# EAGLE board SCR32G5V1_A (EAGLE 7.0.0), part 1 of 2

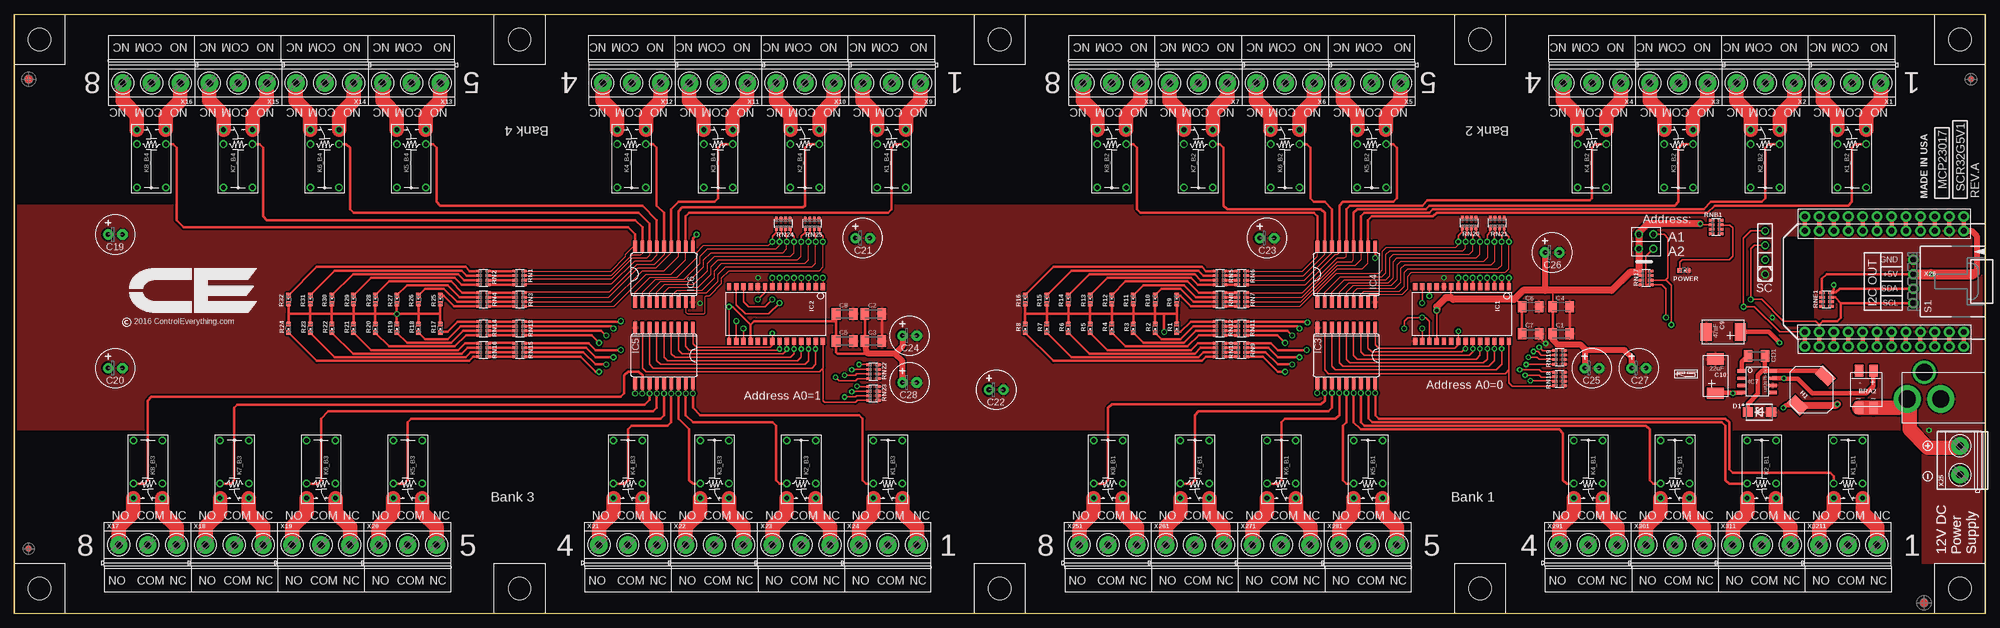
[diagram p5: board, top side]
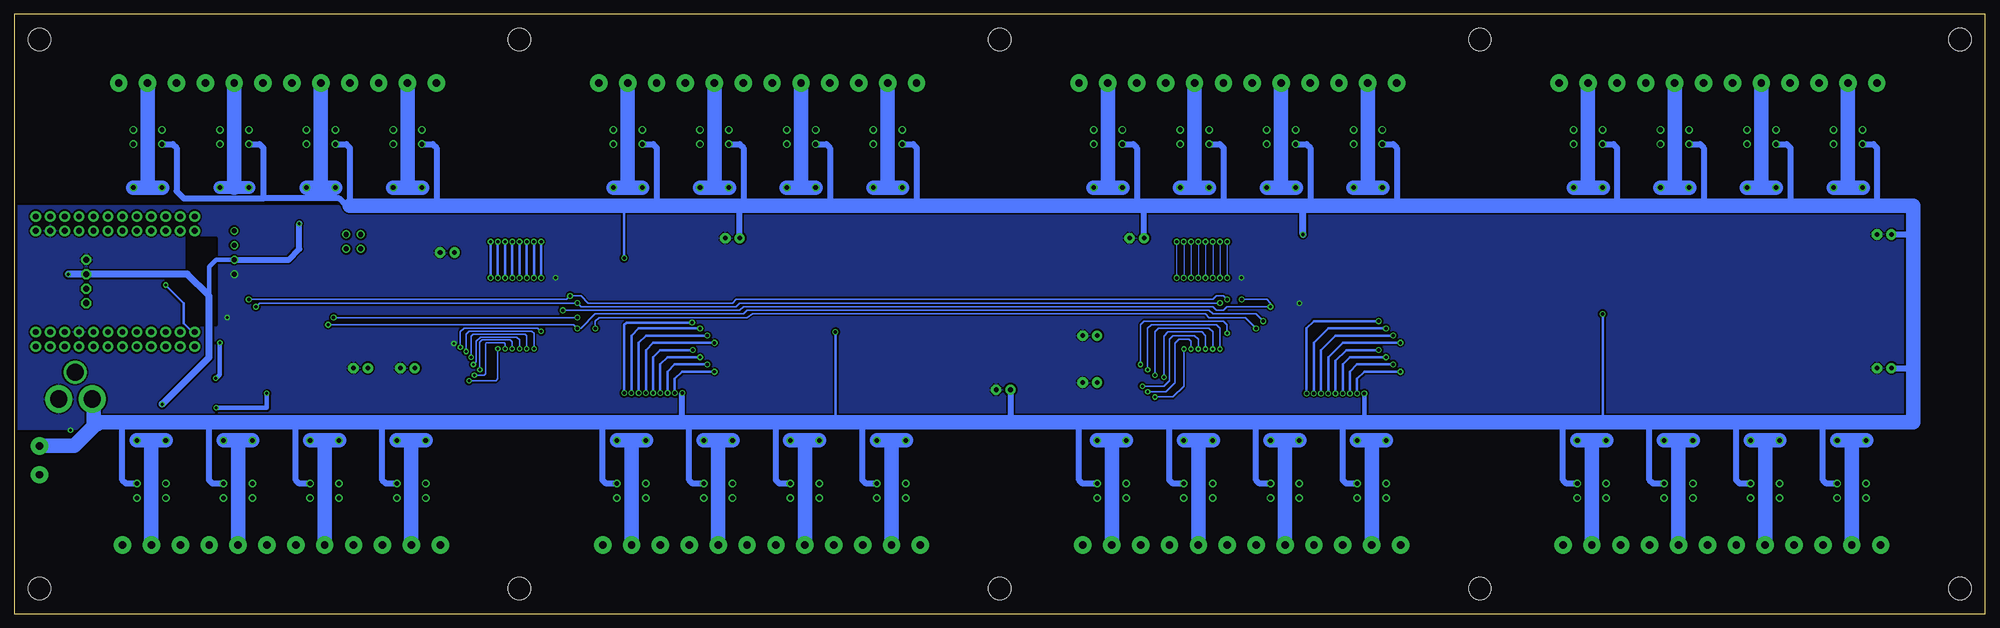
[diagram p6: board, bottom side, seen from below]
Size 346.69 x 105.42 mm. Coordinates in mm from the lower left corner, seen from the top.
Outline: 0,105.42 346.69,105.42 346.69,0 0,0 0,105.42
Copper layers (1*16): Top 0.035mm / dielectric 1.5mm / Bottom 0.035mm
Design rules "default *": minimum track width 6mil, minimum drill 12mil, track to track 5mil, track to pad 5mil, pad to pad 5mil, via to via 5mil, smd to smd 5mil, copper to edge 20mil, drill to drill 8mil, minimum pad ring 10mil, minimum via ring 8mil, stop-mask expansion 4mil, vias tented up to drill 0mil, thermal gap 10mil

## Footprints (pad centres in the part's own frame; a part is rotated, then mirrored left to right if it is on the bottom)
MB2S = smd 1.55 x 2.1: + 0,-6.5; - 2.54,-6.5; ~@1 0,0; ~@2 2.54,0
_CA_.1UF_50V = smd 1.5 x 2: 1 -1.5,0; 2 1.5,0
_CB_10UF_25V = smd 1.5 x 2: 1 -1.5,0; 2 1.5,0
C2917(7343)-Y = smd 2 x 3: 1 -3,0; 2 3,0
E-025X060 = drill 0.813 pad 1.778: + -1.27,0 | drill 0.813 pad 1.778 octagon: - 1.27,0
_CD_10NF_50V = smd 1.5 x 2: 1 -1.5,0; 2 1.5,0
DO214AC_ZENER = smd 1.8 x 1.7: A 2.05,0; C -2.05,0
IND_ELL8TP = smd 2.054 x 3.2 rotated 45: 1 -2.442,-2.696; 2 2.442,2.442
SO28W = smd 0.762 x 1.27: 1 -7.62,-4.78; 2 -6.35,-4.78; 3 -5.08,-4.78; 4 -3.81,-4.78; 5 -2.54,-4.78; 6 -1.27,-4.78; 7 0,-4.78; 8 1.27,-4.78; 9 2.54,-4.78; 10 3.81,-4.78; 11 5.08,-4.78; 12 6.35,-4.78; 13 7.62,-4.78; 14 8.89,-4.78; 15 8.89,4.78; 16 7.62,4.78; 17 6.35,4.78; 18 5.08,4.78; 19 3.81,4.78; 20 2.54,4.78; 21 1.27,4.78; 22 0,4.78; 23 -1.27,4.78; 24 -2.54,4.78; 25 -3.81,4.78; 26 -5.08,4.78; 27 -6.35,4.78; 28 -7.62,4.78
SO18L = smd 0.66 x 2.032: 1 -5.08,-4.902; 2 -3.81,-4.902; 3 -2.54,-4.902; 4 -1.27,-4.902; 5 0,-4.902; 6 1.27,-4.902; 7 2.54,-4.902; 8 3.81,-4.902; 9 5.08,-4.902; 10 5.08,4.902; 11 3.81,4.902; 12 2.54,4.902; 13 1.27,4.902; 14 0,4.902; 15 -1.27,4.902; 16 -2.54,4.902; 17 -3.81,4.902; 18 -5.08,4.902
SO-8 = smd 0.6 x 1.55: 1 -1.905,-2.69; 2 -0.635,-2.69; 3 0.635,-2.69; 4 1.905,-2.69; 5 1.905,2.71; 6 0.635,2.71; 7 -0.635,2.71; 8 -1.905,2.71
G5V1 = drill 0.813: C1 -2.54,2.54; C2 -2.54,-2.54; COM@1 5.08,-2.54; COM@2 5.08,2.54; NC -5.08,-2.54; NO -5.08,2.54
CHIPLED_0603 = smd 0.8 x 0.8: A 0,-0.75; C 0,0.75
RNB = smd 0.5 x 0.9: 1 -1.2,-0.8; 2 -0.4,-0.8; 3 0.4,-0.8; 4 1.2,-0.8; 5 1.2,0.8; 6 0.4,0.8; 7 -0.4,0.8; 8 -1.2,0.8
RNE = smd 0.5 x 0.9: 1 -1.2,-0.8; 2 -0.4,-0.8; 3 0.4,-0.8; 4 1.2,-0.8; 5 1.2,0.8; 6 0.4,0.8; 7 -0.4,0.8; 8 -1.2,0.8
RND = smd 0.5 x 0.9: 1 -1.2,-0.8; 2 -0.4,-0.8; 3 0.4,-0.8; 4 1.2,-0.8; 5 1.2,0.8; 6 0.4,0.8; 7 -0.4,0.8; 8 -1.2,0.8
SPARK_CORE = drill 1.016 pad 1.88: 1 -8.89,13.97; 2 -8.89,11.43; 3 -8.89,8.89; 4 -8.89,6.35; 5 -8.89,3.81; 6 -8.89,1.27; 7 -8.89,-1.27; 8 -8.89,-3.81; 9 -8.89,-6.35; 10 -8.89,-8.89; 11 -8.89,-11.43; 12 -8.89,-13.97; 13 8.89,-13.97; 14 8.89,-11.43; 15 8.89,-8.89; 16 8.89,-6.35; 17 8.89,-3.81; 18 8.89,-1.27; 19 8.89,1.27; 20 8.89,3.81; 21 8.89,6.35; 22 8.89,8.89; 23 8.89,11.43; 24 8.89,13.97; 25 -11.43,13.97; 26 -11.43,11.43; 27 -11.43,8.89; 28 -11.43,6.35; 29 -11.43,3.81; 30 -11.43,1.27; 31 -11.43,-1.27; 32 -11.43,-3.81; 33 -11.43,-6.35; 34 -11.43,-8.89; 35 -11.43,-11.43; 36 -11.43,-13.97; 37 11.43,13.97; 38 11.43,11.43; 39 11.43,8.89; 40 11.43,6.35; 41 11.43,3.81; 42 11.43,1.27; 43 11.43,-1.27; 44 11.43,-3.81; 45 11.43,-6.35; 46 11.43,-8.89; 47 11.43,-11.43; 48 11.43,-13.97
PCB_MOUNTING_HOLE = hole 3.962: 4.445,4.445
JUMPER_2X2 = drill 0.9: A1 0,2.54; A2 0,0; B1 2.54,2.54; B2 2.54,0
PJ-102A = drill 3 pad 4.8: RING 0.1,-3.39; TIP 0.1,-9.29 | drill 3 pad 3.251: RING_SW -4.6,-6.29
MKDSN1,5/3-5,08 = drill 1.3 pad 3.048: 1 -7.641,0.025; 2 -2.561,0.025; 3 2.519,0.025
MKDSN1,5/2-5,08 = drill 1.3 pad 3.048: 1 -2.561,0.025; 2 2.519,0.025
15-91-04 = drill 1.1 pad 1.778 octagon: 1 -3.81,-7.62; 2 -1.27,-7.62; 3 1.27,-7.62; 4 3.81,-7.62

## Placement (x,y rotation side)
BRA2  MB2S_  [MB2S]  327.02,36.21 180 top
C1  [_CA_.1UF_50V]  272.1,49.22 0 top
C2  _CB_10UF_25VC1206K  [_CB_10UF_25V]  151.13,52.72 0 top
C3  [_CA_.1UF_50V]  151.13,47.95 0 top
C4  _CB_10UF_25VC1206K  [_CB_10UF_25V]  272.1,53.99 0 top
C5  [_CA_.1UF_50V]  146.05,47.95 0 top
C6  _CB_10UF_25VC1206K  [_CB_10UF_25V]  266.7,53.99 0 top
C7  [_CA_.1UF_50V]  266.7,49.22 0 top
C8  _CB_10UF_25VC1206K  [_CB_10UF_25V]  146.05,52.72 0 top
C9  47uF  [C2917(7343)-Y]  300.61,49.54 180 top
C10  22uF  [C2917(7343)-Y]  299.21,41.77 90 top
C19  100uF  [E-025X060]  17.78,66.69 0 top
C20  100uF  [E-025X060]  17.78,43.19 0 top
C21  100uF  [E-025X060]  149.22,66.05 0 top
C22  100uF  [E-025X060]  172.72,39.38 0 top
C23  100uF  [E-025X060]  220.34,66.05 0 top
C24  100uF  [E-025X060]  157.48,48.91 0 top
C25  100uF  [E-025X060]  277.5,43.19 0 top
C26  100uF  [E-025X060]  270.51,63.51 0 top
C27  100uF  [E-025X060]  285.75,43.19 0 top
C28  100uF  [E-025X060]  157.48,40.65 0 top
CD1  [_CD_10NF_50V]  306.45,45.35 0 top
D1  B360A  [DO214AC_ZENER]  306.96,35.45 0 top
H1  ELL8TP  [IND_ELL8TP]  316.1,39.38 0 top
IC1  MCP23017SO  [SO28W]  255.27,52.72 180 top
IC2  MCP23017SO  [SO28W]  134.62,52.72 180 top
IC3  ULN2803  [SO18L]  234.31,45.42 180 top
IC4  ULN2803  [SO18L]  234.31,59.7 0 top
IC5  ULN2803  [SO18L]  114.3,45.42 180 top
IC6  ULN2803  [SO18L]  114.3,59.7 0 top
IC7  LM2675-5V  [SO-8]  306.58,40.78 270 top
K1_B1  G5V1  [G5V1]  322.58,25.41 90 top
K1_B2  G5V1  [G5V1]  323.21,80.02 270 top
K1_B3  G5V1  [G5V1]  153.67,25.41 90 top
K1_B4  G5V1  [G5V1]  154.31,80.02 270 top
K2_B1  G5V1  [G5V1]  307.34,25.41 90 top
K2_B2  G5V1  [G5V1]  307.98,80.02 270 top
K2_B3  G5V1  [G5V1]  138.43,25.41 90 top
K2_B4  G5V1  [G5V1]  139.06,80.02 270 top
K3_B1  G5V1  [G5V1]  292.1,25.41 90 top
K3_B2  G5V1  [G5V1]  292.74,80.02 270 top
K3_B3  G5V1  [G5V1]  123.19,25.41 90 top
K3_B4  G5V1  [G5V1]  123.83,80.02 270 top
K4_B1  G5V1  [G5V1]  276.86,25.41 90 top
K4_B2  G5V1  [G5V1]  277.5,80.02 270 top
K4_B3  G5V1  [G5V1]  107.95,25.41 90 top
K4_B4  G5V1  [G5V1]  108.58,80.02 270 top
K5_B1  G5V1  [G5V1]  238.12,25.41 90 top
K5_B2  G5V1  [G5V1]  238.76,80.02 270 top
K5_B3  G5V1  [G5V1]  69.22,25.41 90 top
K5_B4  G5V1  [G5V1]  69.85,80.02 270 top
K6_B1  G5V1  [G5V1]  222.88,25.41 90 top
K6_B2  G5V1  [G5V1]  223.52,80.02 270 top
K6_B3  G5V1  [G5V1]  53.98,25.41 90 top
K6_B4  G5V1  [G5V1]  54.61,80.02 270 top
K7_B1  G5V1  [G5V1]  207.65,25.41 90 top
K7_B2  G5V1  [G5V1]  208.28,80.02 270 top
K7_B3  G5V1  [G5V1]  38.73,25.41 90 top
K7_B4  G5V1  [G5V1]  39.37,80.02 270 top
K8_B1  G5V1  [G5V1]  192.41,25.41 90 top
K8_B2  G5V1  [G5V1]  193.04,80.02 270 top
K8_B3  G5V1  [G5V1]  23.5,25.41 90 top
K8_B4  G5V1  [G5V1]  24.13,80.02 270 top
POWER  LED_NCD  [CHIPLED_0603]  293.69,60.34 270 top
R1  LED_NCD  [CHIPLED_0603]  204.47,50.18 180 top
R2  LED_NCD  [CHIPLED_0603]  200.66,50.18 180 top
R3  LED_NCD  [CHIPLED_0603]  196.85,50.18 180 top
R4  LED_NCD  [CHIPLED_0603]  193.04,50.18 180 top
R5  LED_NCD  [CHIPLED_0603]  189.23,50.18 180 top
R6  LED_NCD  [CHIPLED_0603]  185.42,50.18 180 top
R7  LED_NCD  [CHIPLED_0603]  181.61,50.18 180 top
R8  LED_NCD  [CHIPLED_0603]  177.8,50.18 180 top
R9  LED_NCD  [CHIPLED_0603]  204.47,55.26 0 top
R10  LED_NCD  [CHIPLED_0603]  200.66,55.26 0 top
R11  LED_NCD  [CHIPLED_0603]  196.85,55.26 0 top
R12  LED_NCD  [CHIPLED_0603]  193.04,55.26 0 top
R13  LED_NCD  [CHIPLED_0603]  189.23,55.26 0 top
R14  LED_NCD  [CHIPLED_0603]  185.42,55.26 0 top
R15  LED_NCD  [CHIPLED_0603]  181.61,55.26 0 top
R16  LED_NCD  [CHIPLED_0603]  177.8,55.26 0 top
R17  LED_NCD  [CHIPLED_0603]  74.93,50.18 180 top
R18  LED_NCD  [CHIPLED_0603]  71.12,50.18 180 top
R19  LED_NCD  [CHIPLED_0603]  67.31,50.18 180 top
R20  LED_NCD  [CHIPLED_0603]  63.5,50.18 180 top
R21  LED_NCD  [CHIPLED_0603]  59.69,50.18 180 top
R22  LED_NCD  [CHIPLED_0603]  55.88,50.18 180 top
R23  LED_NCD  [CHIPLED_0603]  52.07,50.18 180 top
R24  LED_NCD  [CHIPLED_0603]  48.26,50.18 180 top
R25  LED_NCD  [CHIPLED_0603]  74.93,55.26 0 top
R26  LED_NCD  [CHIPLED_0603]  71.12,55.26 0 top
R27  LED_NCD  [CHIPLED_0603]  67.31,55.26 0 top
R28  LED_NCD  [CHIPLED_0603]  63.5,55.26 0 top
R29  LED_NCD  [CHIPLED_0603]  59.69,55.26 0 top
R30  LED_NCD  [CHIPLED_0603]  55.88,55.26 0 top
R31  LED_NCD  [CHIPLED_0603]  52.07,55.26 0 top
R32  LED_NCD  [CHIPLED_0603]  48.26,55.26 0 top
RN1  _RNB_510  [RNB]  88.9,59.07 90 top
RN2  _RNB_510  [RNB]  82.55,59.07 90 top
RN3  _RNB_510  [RNB]  88.9,55.26 270 top
RN4  _RNB_510  [RNB]  82.55,55.26 270 top
RN5  _RNB_510  [RNB]  212.09,59.07 270 top
RN6  _RNB_510  [RNB]  215.9,59.07 270 top
RN7  _RNB_510  [RNB]  215.9,55.26 270 top
RN8  _RNB_510  [RNB]  212.09,55.26 270 top
RN9  _RNB_510  [RNB]  215.9,46.37 270 top
RN10  _RNB_510  [RNB]  212.09,46.37 270 top
RN11  _RNB_510  [RNB]  215.9,50.18 90 top
RN12  _RNB_510  [RNB]  212.09,50.18 90 top
RN13  _RNB_510  [RNB]  88.9,50.18 270 top
RN14  _RNB_510  [RNB]  82.55,50.18 270 top
RN15  _RNB_510  [RNB]  88.9,46.37 270 top
RN16  _RNB_510  [RNB]  82.55,46.37 270 top
RN17  _RNE_10K  [RNE]  287.02,59.07 270 top
RN18  _RNE_10K  [RNE]  271.78,41.29 90 top
RN19  _RNE_10K  [RNE]  271.78,45.1 90 top
RN20  _RNE_10K  [RNE]  255.91,68.72 180 top
RN21  _RNE_10K  [RNE]  260.86,68.72 180 top
RN22  _RNE_10K  [RNE]  151.13,42.56 90 top
RN23  _RNE_10K  [RNE]  151.13,38.75 90 top
RN24  _RNE_10K  [RNE]  135.25,68.59 180 top
RN25  _RNE_10K  [RNE]  140.34,68.59 180 top
RNB1  _RNB_510  [RNB]  299.34,68.02 90 top
RNE1  _RND_4.7K  [RND]  318.77,55.26 90 top
S1  [SPARK_CORE]  328.93,58.43 270 top
U$1  PCB_MOUNTING_HOLE  [PCB_MOUNTING_HOLE]  262.25,96.53 90 top
U$2  PCB_MOUNTING_HOLE  [PCB_MOUNTING_HOLE]  177.8,96.53 90 top
U$3  PCB_MOUNTING_HOLE  [PCB_MOUNTING_HOLE]  346.71,96.53 90 top
U$4  PCB_MOUNTING_HOLE  [PCB_MOUNTING_HOLE]  84.45,8.9 270 top
U$5  PCB_MOUNTING_HOLE  [PCB_MOUNTING_HOLE]  168.91,8.9 270 top
U$6  PCB_MOUNTING_HOLE  [PCB_MOUNTING_HOLE]  0,8.9 270 top
U$7  PCB_MOUNTING_HOLE  [PCB_MOUNTING_HOLE]  93.34,96.53 90 top
U$8  PCB_MOUNTING_HOLE  [PCB_MOUNTING_HOLE]  8.89,96.53 90 top
U$9  PCB_MOUNTING_HOLE  [PCB_MOUNTING_HOLE]  177.8,96.53 90 top
U$10  PCB_MOUNTING_HOLE  [PCB_MOUNTING_HOLE]  253.37,8.9 270 top
U$11  PCB_MOUNTING_HOLE  [PCB_MOUNTING_HOLE]  337.82,8.9 270 top
U$12  PCB_MOUNTING_HOLE  [PCB_MOUNTING_HOLE]  168.91,8.9 270 top
U$13  JUMPER_2X2  [JUMPER_2X2]  285.75,66.69 270 top
U$14  2.1MMJACK  [PJ-102A]  342.26,37.86 270 top
U$15  [VISION_REF15]  335.92,1.92 90 top
U$18  [VISION_REF10]  344.17,93.99 90 top
U$19  [ICON_MINUS]  336.55,24.14 90 top
U$20  [ICON_PLUS]  336.55,29.54 0 top
U$21  [ICON_USA]  336.55,73.04 90 top
U$22  [ICON_MINUS]  336.55,24.14 90 top
U$23  [VISION_REF15]  2.54,93.99 90 top
U$24  [ICON_PLUS]  336.55,29.54 0 top
U$28  [VISION_REF10]  2.54,11.44 90 top
X1  MKDSN1,5/3-5,08  [MKDSN1,5/3-5,08]  320.68,93.36 180 top
X2  MKDSN1,5/3-5,08  [MKDSN1,5/3-5,08]  305.44,93.36 180 top
X3  MKDSN1,5/3-5,08  [MKDSN1,5/3-5,08]  290.19,93.36 180 top
X4  MKDSN1,5/3-5,08  [MKDSN1,5/3-5,08]  274.95,93.36 180 top
X5  MKDSN1,5/3-5,08  [MKDSN1,5/3-5,08]  236.22,93.36 180 top
X6  MKDSN1,5/3-5,08  [MKDSN1,5/3-5,08]  220.98,93.36 180 top
X7  MKDSN1,5/3-5,08  [MKDSN1,5/3-5,08]  205.74,93.36 180 top
X8  MKDSN1,5/3-5,08  [MKDSN1,5/3-5,08]  190.5,93.36 180 top
X9  MKDSN1,5/3-5,08  [MKDSN1,5/3-5,08]  151.76,93.36 180 top
X10  MKDSN1,5/3-5,08  [MKDSN1,5/3-5,08]  136.53,93.36 180 top
X11  MKDSN1,5/3-5,08  [MKDSN1,5/3-5,08]  121.28,93.36 180 top
X12  MKDSN1,5/3-5,08  [MKDSN1,5/3-5,08]  106.05,93.36 180 top
X13  MKDSN1,5/3-5,08  [MKDSN1,5/3-5,08]  67.31,93.36 180 top
X14  MKDSN1,5/3-5,08  [MKDSN1,5/3-5,08]  52.07,93.36 180 top
X15  MKDSN1,5/3-5,08  [MKDSN1,5/3-5,08]  36.83,93.36 180 top
X16  MKDSN1,5/3-5,08  [MKDSN1,5/3-5,08]  21.59,93.36 180 top
X17  MKDSN1,5/3-5,08  [MKDSN1,5/3-5,08]  26.04,12.08 0 top
X18  MKDSN1,5/3-5,08  [MKDSN1,5/3-5,08]  41.27,12.08 0 top
X19  MKDSN1,5/3-5,08  [MKDSN1,5/3-5,08]  56.52,12.08 0 top
X20  MKDSN1,5/3-5,08  [MKDSN1,5/3-5,08]  71.75,12.08 0 top
X21  MKDSN1,5/3-5,08  [MKDSN1,5/3-5,08]  110.49,12.08 0 top
X22  MKDSN1,5/3-5,08  [MKDSN1,5/3-5,08]  125.73,12.08 0 top
X23  MKDSN1,5/3-5,08  [MKDSN1,5/3-5,08]  140.97,12.08 0 top
X24  MKDSN1,5/3-5,08  [MKDSN1,5/3-5,08]  156.21,12.08 0 top
X25  MKDSN1,5/2-5,08  [MKDSN1,5/2-5,08]  342.26,27 90 top
X26  C-GRID-04-15-91-3044  [15-91-04]  341.63,58.43 270 top
X251  MKDSN1,5/3-5,08  [MKDSN1,5/3-5,08]  194.94,12.08 0 top
X261  MKDSN1,5/3-5,08  [MKDSN1,5/3-5,08]  210.19,12.08 0 top
X271  MKDSN1,5/3-5,08  [MKDSN1,5/3-5,08]  225.43,12.08 0 top
X281  MKDSN1,5/3-5,08  [MKDSN1,5/3-5,08]  240.66,12.08 0 top
X291  MKDSN1,5/3-5,08  [MKDSN1,5/3-5,08]  279.4,12.08 0 top
X301  MKDSN1,5/3-5,08  [MKDSN1,5/3-5,08]  294.64,12.08 0 top
X311  MKDSN1,5/3-5,08  [MKDSN1,5/3-5,08]  309.88,12.08 0 top
X3211  MKDSN1,5/3-5,08  [MKDSN1,5/3-5,08]  325.12,12.08 0 top

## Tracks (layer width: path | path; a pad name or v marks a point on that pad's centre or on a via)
GND  (via drill 0.5, 0.9)
  Top 0.305: v269.37,47.51 268.61,48.27 268.61,48.82 C7.2
  Top 0.406: C1.2 C4.2 | C3.2 C2.2
  other vias: 120.65,54.62 336.8,32.27 307.98,59.7 309.25,52.08 251.46,59.07 130.81,59.07
  pour Top (isolate 0.305): -2.54,32.4 -2.54,71.77 346.39,71.77 346.39,32.4
  pour Top: 346.39,20.33 335.6,20.33 335.6,32.4 346.39,32.4
  pour Bottom (isolate 0.305): -5.71,32.4 -5.71,71.77 346.07,71.77 346.07,32.4
  pour Top: 346.39,8.9 335.6,8.9 335.6,32.4 346.39,32.4
I2C_SCL  (via drill 0.6, 0.9)
  Top 0.254: 317.5,50.81 316.87,51.45 311.15,51.45 307.34,55.26 v305.44,55.26 305.44,64.15 306.07,64.78 v307.98,64.78
  Top 0.305: IC2.12 128.27,54.89 129.17,53.99 132.08,53.99 v133.35,55.26 | v248.92,55.89 IC1.12
  Top 0.406: X26.4 321.31,54.62 | 321.31,54.62 320.29,55.64 319.59,55.64 RNE1.3 | S1.14 317.5,50.81 318.13,51.45 320.68,51.45 321.31,52.08 321.31,54.62
  Bottom 0.305: v305.44,55.26 249.56,55.26 v248.92,55.89 247.01,55.89 245.75,54.62 220.34,54.62 219.71,55.26 135.89,55.26 135.25,55.89 133.99,55.89 v133.35,55.26
I2C_SDA  (via drill 0.5, 0.6, 0.9)
  Top 0.254: S1.13 310.51,49.54 306.07,53.99 v304.17,53.99 304.17,66.05 305.44,67.32 v307.98,67.32
  Top 0.305: IC2.13 127,54.37 128.66,52.72 132.72,52.72 v134.62,54.62 | v247.65,54.62 IC1.13
  Top 0.406: X26.3 321.06,57.16 320.42,56.53 319.64,56.53 RNE1.4 320.04,56.93 v320.04,57.8
  Bottom 0.305: v134.62,54.62 219.07,54.62 219.71,53.99 247.01,53.99 v247.65,54.62 303.53,54.62 v304.17,53.99
  Bottom 0.406: S1.13 315.34,49.54 316.87,51.07 316.87,54.62 v320.04,57.8
N$1
  Bottom 2.54: K8_B2.COM@1 193.04,74.94 | 193.04,74.94 K8_B2.COM@2 | X8.2 193.06,74.96 193.04,74.94
N$2
  Top 2.54: K8_B2.NC 190.5,87.64 187.96,90.18 187.96,93.31 X8.3
N$3
  Top 2.54: K8_B2.NO 195.58,87.64 198.12,90.18 198.12,93.31 X8.1
N$4
  Top 2.54: K7_B2.NO 210.82,88.28 213.36,90.82 213.36,93.31 X7.1
N$5
  Top 2.54: K6_B2.NO 226.06,87.64 228.6,90.18 228.6,93.31 X6.1
N$6
  Top 2.54: K7_B2.NC 205.74,87.64 203.2,90.18 203.2,93.31 X7.3
N$7
  Bottom 2.54: K7_B2.COM@1 208.28,74.94 | 208.28,74.94 K7_B2.COM@2 | X7.2 208.3,74.96 208.28,74.94
N$8
  Top 2.54: K6_B2.NC 220.98,87.64 218.44,90.18 218.44,93.31 X6.3
N$9
  Top 0.254: POWER.A 292.94,61.81 293.37,62.24 301.62,62.24 302.26,62.88 302.26,67.83 301.75,68.34 300.22,68.34 RNB1.3
N$10
  Top 2.54: K4_B2.NO 280.04,87.64 282.57,90.18 282.57,93.31 X4.1
N$11
  Top 2.54: K4_B2.NC 274.95,87.64 272.42,90.18 272.42,93.31 X4.3
N$12
  Bottom 2.54: K4_B2.COM@1 277.5,74.94 | 277.5,74.94 K4_B2.COM@2 | X4.2 277.52,74.96 277.5,74.94
N$13
  Top 0.813: 307.98,42.68 IC7.8 317.69,42.68 H1.2 | 307.98,42.68 307.47,42.68 306.7,41.92 306.7,38.65 304.93,36.87 304.93,35.46 D1.C | CD1.2 307.95,42.71 307.98,42.68
N$14
  Bottom 2.54: K6_B2.COM@1 223.52,74.94 | 223.52,74.94 K6_B2.COM@2 | X6.2 223.54,74.96 223.52,74.94
N$15
  Top 0.813: IC7.1 303.89,44.29 CD1.1
N$33
  Top 2.54: K5_B2.NC 236.22,87.64 233.68,90.18 233.68,93.31 X5.3
N$34
  Bottom 2.54: K5_B2.COM@2 238.76,74.94 | 238.76,74.94 K5_B2.COM@1 | X5.2 238.78,74.96 238.76,74.94
N$35
  Top 2.54: K5_B2.NO 241.3,87.64 243.84,90.18 243.84,93.31 X5.1
N$36
  Top 2.54: K3_B2.NO 295.27,87.64 297.81,90.18 297.81,93.31 X3.1
N$37
  Top 2.54: K3_B2.NC 290.19,87.64 287.65,90.18 287.65,93.31 X3.3
N$38
  Bottom 2.54: K3_B2.COM@1 292.74,74.94 | 292.74,74.94 K3_B2.COM@2 | X3.2 292.76,74.96 292.74,74.94
N$39
  Top 2.54: K2_B2.NO 310.51,87.64 313.06,90.18 313.06,93.31 X2.1
N$40
  Top 2.54: K2_B2.NC 305.44,87.64 302.89,90.18 302.89,93.31 X2.3
N$41
  Bottom 2.286: K2_B2.COM@1 307.98,74.94 K2_B2.COM@2
  Bottom 2.54: X2.2 308,74.96 307.98,74.94
N$42
  Top 2.54: K1_B2.NO 325.75,87.64 328.3,90.18 328.3,93.31 X1.1
N$43
  Top 2.54: K1_B2.NC 320.68,87.64 318.13,90.18 318.13,93.31 X1.3
N$44
  Bottom 2.54: K1_B2.COM@1 323.21,74.94 | 323.21,74.94 K1_B2.COM@2 | X1.2 323.24,74.96 323.21,74.94
N$78
  Bottom 2.54: K1_B4.COM@1 154.31,74.94 | 154.31,74.94 K1_B4.COM@2 | X9.2 154.33,74.96 154.31,74.94
N$79
  Top 2.54: K1_B4.NC 151.76,87.64 149.22,90.18 149.22,93.31 X9.3
N$80
  Top 2.54: K1_B4.NO 156.84,87.64 159.38,90.18 159.38,93.31 X9.1
N$81
  Top 2.54: K2_B4.NO 141.6,87.64 144.15,90.18 144.15,93.31 X10.1
N$82
  Top 2.54: K3_B4.NO 126.36,87.64 128.91,90.18 128.91,93.31 X11.1
N$83
  Top 2.54: K2_B4.NC 136.53,87.64 133.99,90.18 133.99,93.31 X10.3
N$84
  Bottom 2.54: K2_B4.COM@1 139.06,74.94 | 139.06,74.94 K2_B4.COM@2 | X10.2 139.09,74.96 139.06,74.94
N$85
  Top 2.54: K3_B4.NC 121.28,87.64 118.75,90.18 118.75,93.31 X11.3
N$86
  Bottom 2.54: K3_B4.COM@1 123.83,74.94 | 123.83,74.94 K3_B4.COM@2 | X11.2 123.85,74.96 123.83,74.94
N$87
  Top 2.54: K4_B4.NC 106.05,87.64 103.5,90.18 103.5,93.31 X12.3
N$88
  Bottom 2.54: K4_B4.COM@1 107.95,74.94 | 107.95,74.94 K4_B4.COM@2 | X12.2 108.61,75.6 107.95,74.94
N$89
  Top 2.54: K4_B4.NO 111.12,87.64 113.67,90.18 113.67,93.31 X12.1
N$90
  Top 2.54: K5_B4.NO 72.39,87.64 74.93,90.18 74.93,93.31 X13.1
N$91
  Top 2.54: K5_B4.NC 67.31,87.64 64.77,90.18 64.77,93.31 X13.3
N$92
  Bottom 2.54: K5_B4.COM@1 69.85,74.94 | 69.85,74.94 K5_B4.COM@2 | X13.2 69.87,74.96 69.85,74.94
N$93
  Top 2.54: K6_B4.NO 57.15,87.64 59.69,90.18 59.69,93.31 X14.1
N$94
  Top 2.54: K6_B4.NC 52.07,87.64 49.53,90.18 49.53,93.31 X14.3
N$95
  Bottom 2.54: K6_B4.COM@1 54.61,74.94 | 54.61,74.94 K6_B4.COM@2 | X14.2 54.63,74.96 54.61,74.94
N$96
  Top 2.54: K7_B4.NO 41.91,87.64 44.45,90.18 44.45,93.31 X15.1
N$97
  Top 2.54: K7_B4.NC 36.83,87.64 34.29,90.18 34.29,93.31 X15.3
N$98
  Bottom 2.54: K7_B4.COM@1 40.01,74.94 | 40.01,74.94 K7_B4.COM@2 | X15.2 39.39,75.56 40.01,74.94
N$99
  Top 2.54: K8_B4.NO 26.67,87.64 29.21,90.18 29.21,93.31 X16.1
N$100
  Top 2.54: K8_B4.NC 21.59,87.64 19.05,90.18 19.05,93.31 X16.3
N$101
  Bottom 2.54: K8_B4.COM@1 24.13,74.94 | 24.13,74.94 K8_B4.COM@2 | X16.2 24.15,74.96 24.13,74.94
N$179
  Bottom 2.54: K8_B3.COM@2 23.5,30.49 | 23.5,30.49 K8_B3.COM@1 | X17.2 23.47,30.47 23.5,30.49
N$180
  Top 2.54: K8_B3.NC 26.04,17.79 28.57,15.25 28.57,12.12 X17.3
N$181
  Top 2.54: K8_B3.NO 20.95,17.79 18.41,15.25 18.41,12.12 X17.1
N$182
  Top 2.54: K7_B3.NO 36.2,17.79 33.66,15.25 33.66,12.12 X18.1
N$183
  Top 2.54: K6_B3.NO 51.44,17.79 48.9,15.25 48.9,12.12 X19.1
N$184
  Top 2.54: K7_B3.NC 41.27,17.79 43.81,15.25 43.81,12.12 X18.3
N$185
  Bottom 2.54: K7_B3.COM@2 38.73,30.49 | 38.73,30.49 K7_B3.COM@1 | X18.2 38.71,30.47 38.73,30.49
N$186
  Top 2.54: K6_B3.NC 56.52,17.79 59.05,15.25 59.05,12.12 X19.3
N$187
  Bottom 2.54: K6_B3.COM@1 54.61,30.49 | 54.61,30.49 K6_B3.COM@2 | X19.2 53.95,29.84 54.61,30.49
N$188
  Top 2.54: K5_B3.NC 71.75,17.79 74.3,15.25 74.3,12.12 X20.3
N$189
  Bottom 2.54: K5_B3.COM@1 69.22,30.49 | 69.22,30.49 K5_B3.COM@2 | X20.2 69.19,30.47 69.22,30.49
N$190
  Top 2.54: K5_B3.NO 66.67,17.79 64.14,15.25 64.14,12.12 X20.1
N$191
  Top 2.54: K4_B3.NO 105.41,17.79 102.87,15.25 102.87,12.12 X21.1
N$192
  Top 2.54: K4_B3.NC 110.49,17.79 113.03,15.25 113.03,12.12 X21.3
N$193
  Bottom 2.54: K4_B3.COM@2 107.95,30.49 | 107.95,30.49 K4_B3.COM@1 | X21.2 107.93,30.47 107.95,30.49
N$194
  Top 2.54: K3_B3.NO 120.65,17.79 118.11,15.25 118.11,12.12 X22.1
N$195
  Top 2.54: K3_B3.NC 125.73,17.79 128.27,15.25 128.27,12.12 X22.3
N$196
  Bottom 2.54: K3_B3.COM@2 123.19,30.49 | 123.19,30.49 K3_B3.COM@1 | X22.2 123.17,30.47 123.19,30.49
N$197
  Top 2.54: K2_B3.NO 135.89,17.79 133.35,15.25 133.35,12.12 X23.1
N$198
  Top 2.54: K2_B3.NC 140.97,17.79 143.51,15.25 143.51,12.12 X23.3
N$199
  Bottom 2.54: K2_B3.COM@2 137.79,30.49 | 137.79,30.49 K2_B3.COM@1 | X23.2 138.41,29.88 137.79,30.49
N$200
  Top 2.54: K1_B3.NO 151.13,17.79 148.59,15.25 148.59,12.12 X24.1
N$201
  Top 2.54: K1_B3.NC 156.21,17.79 158.75,15.25 158.75,12.12 X24.3
N$202
  Bottom 2.54: K1_B3.COM@1 153.67,30.49 | 153.67,30.49 K1_B3.COM@2 | X24.2 153.65,30.47 153.67,30.49
N$203
  Bottom 2.54: K8_B1.COM@2 192.41,30.49 | 192.41,30.49 K8_B1.COM@1 | X251.2 192.38,30.47 192.41,30.49
N$204
  Top 2.54: K8_B1.NC 194.94,17.79 197.49,15.25 197.49,12.12 X251.3
N$205
  Top 2.54: K8_B1.NO 189.87,17.79 187.32,15.25 187.32,12.12 X251.1
N$206
  Top 2.54: K7_B1.NO 205.1,17.79 202.56,15.25 202.56,12.12 X261.1
N$207
  Top 2.54: K6_B1.NO 220.34,17.79 217.81,15.25 217.81,12.12 X271.1
N$208
  Top 2.54: K7_B1.NC 210.19,17.79 212.72,15.25 212.72,12.12 X261.3
N$209
  Bottom 2.54: K7_B1.COM@1 207.65,30.49 | 207.65,30.49 K7_B1.COM@2 | X261.2 207.62,30.47 207.65,30.49
N$210
  Top 2.54: K6_B1.NC 225.43,17.79 227.97,15.25 227.97,12.12 X271.3
N$211
  Bottom 2.54: K6_B1.COM@1 222.88,30.49 | 222.88,30.49 K6_B1.COM@2 | X271.2 222.86,30.47 222.88,30.49
N$212
  Top 2.54: K5_B1.NC 240.66,17.79 243.21,15.25 243.21,12.12 X281.3
N$213
  Bottom 2.54: K5_B1.COM@1 238.12,30.49 | 238.12,30.49 K5_B1.COM@2 | X281.2 238.1,30.47 238.12,30.49
N$214
  Top 2.54: K5_B1.NO 235.59,17.79 233.04,15.25 233.04,12.12 X281.1
N$215
  Top 2.54: K4_B1.NO 274.32,17.79 271.78,15.25 271.78,12.12 X291.1
N$216
  Top 2.54: K4_B1.NC 279.4,17.79 281.94,15.25 281.94,12.12 X291.3
N$217
  Bottom 2.54: K4_B1.COM@2 276.86,30.49 | 276.86,30.49 K4_B1.COM@1 | X291.2 276.84,30.47 276.86,30.49
N$218
  Top 2.54: K3_B1.NO 289.56,17.79 287.02,15.25 287.02,12.12 X301.1
N$219
  Top 2.54: K3_B1.NC 294.64,17.79 297.18,15.25 297.18,12.12 X301.3
N$220
  Bottom 2.54: K3_B1.COM@2 292.1,30.49 | 292.1,30.49 K3_B1.COM@1 | X301.2 292.08,30.47 292.1,30.49
N$221
  Top 2.54: K2_B1.NO 304.8,17.79 302.26,15.25 302.26,12.12 X311.1
N$222
  Top 2.54: K2_B1.NC 309.88,17.79 312.42,15.25 312.42,12.12 X311.3
N$223
  Bottom 2.54: K2_B1.COM@1 307.34,30.49 | 307.34,30.49 K2_B1.COM@2 | X311.2 307.32,30.47 307.34,30.49
N$224
  Top 2.54: K1_B1.NO 320.04,17.79 317.5,15.25 317.5,12.12 X3211.1
N$225
  Top 2.54: K1_B1.NC 325.12,17.79 327.66,15.25 327.66,12.12 X3211.3
N$226
  Bottom 2.54: K1_B1.COM@1 322.58,30.49 | 322.58,30.49 K1_B1.COM@2 | X3211.2 322.56,30.47 322.58,30.49
N$405  (via drill 0.5)
  Top 0.229: IC1.21 254,47.32 253.37,46.68 240.03,46.68 239.4,47.32 IC3.1
  Top 0.254: 254,47.32 v254,49.67 | v268.22,46.88 268.86,46.24 270.92,46.24
  Top 0.305: 270.92,46.24 270.98,46.24 RN19.5
  Bottom 0.229: v254,49.67 254,49.54 254.63,50.18 267.59,50.18 268.22,49.54 v268.22,46.88
N$406  (via drill 0.5)
  Top 0.229: IC1.25 v259.09,46.62 259.08,44.78 258.44,44.14 234.95,44.14 234.31,44.78 IC3.5 | v264.8,42.88 268.29,42.88 268.61,42.56 270.91,42.56 RN18.5
  Bottom 0.229: v259.09,46.62 259.08,47.79 259.44,48.15 264.39,48.15 264.8,47.74 v264.8,42.88
N$407  (via drill 0.5)
  Top 0.229: IC1.26 v260.35,46.62 260.35,44.46 259.4,43.51 233.68,43.51 233.04,44.14 IC3.6 | v265.75,41.92 268.29,41.92 268.61,41.6 270.9,41.6 RN18.6
  Bottom 0.229: v260.35,46.62 260.35,47.51 260.48,47.64 263.65,47.64 263.78,47.51 263.78,42.18 264.03,41.92 v265.75,41.92
N$408  (via drill 0.6)
  Top 0.305: IC2.16 v127,51.45 | v247.65,50.18 IC1.16 | RN17.6 290.43,58.67 | 290.43,58.67 290.83,59.07 290.83,66.05 290.19,66.69 U$13.A1 | 290.43,58.67 290.6,58.67 291.46,57.8 v291.46,50.81
  Bottom 0.305: v127,51.45 128.27,52.72 135.89,52.72 136.53,53.35 217.81,53.35 218.44,52.72 244.47,52.72 247.01,50.18 v247.65,50.18 248.28,50.81 v291.46,50.81
N$409  (via drill 0.5)
  Top 0.229: IC1.22 255.27,46.68 254.63,46.05 238.76,46.05 238.12,46.68 IC3.2
  Top 0.254: 255.27,46.68 v255.27,46.62 | v267.21,46.11 267.97,46.11 268.61,45.48 270.96,45.48 RN19.6
  Bottom 0.229: v255.27,46.62 255.27,49.29 255.65,49.67 266.7,49.67 267.21,49.16 v267.21,46.11
N$410  (via drill 0.5)
  Top 0.229: IC1.23 256.54,46.05 255.91,45.42 237.49,45.42 236.85,46.05 IC3.3
  Top 0.254: 256.54,46.05 v256.54,46.62 | v266.32,45.1 267.84,45.1 268.22,44.72 270.96,44.72 RN19.7
  Bottom 0.229: v256.54,46.62 256.54,48.91 256.79,49.16 265.94,49.16 266.32,48.78 v266.32,45.1
  Bottom 0.254: 266.57,44.97 v266.32,45.1
N$411  (via drill 0.5)
  Top 0.229: IC1.24 257.81,45.42 257.18,44.78 236.22,44.78 235.59,45.42 IC3.4
  Top 0.254: 257.81,45.42 v257.81,46.62 | v265.94,43.83 270.91,43.83 RN19.8
  Bottom 0.229: v257.81,46.62 257.81,48.15 258.32,48.65 264.67,48.65 265.43,47.89 265.43,44.34 v265.94,43.83
N$416  (via drill 0.6)
  Top 0.203: 238.12,55.89 238.44,56.21 244.16,56.21 245.11,57.16 245.11,59.38 245.75,60.02 262.25,60.02 262.89,60.66 v262.89,65.42
  Top 0.229: v262.89,65.42 262.89,66.31 262.13,67.07 262.13,67.85 RN21.8
  Top 0.406: v262.89,59.07 IC1.1 | IC4.8 238.12,55.89
  Bottom 0.406: v262.89,65.42 v262.89,59.07
N$417  (via drill 0.6)
  Top 0.203: IC4.7 236.85,56.21 237.36,56.72 243.65,56.72 244.47,57.54 244.47,60.02 245.11,60.66 260.99,60.66 261.62,61.29 v261.62,65.42
  Top 0.229: v261.62,65.42 261.62,66.43 261.24,66.81 261.24,67.9 RN21.7
  Top 0.406: v261.62,59.07 IC1.2
  Bottom 0.406: v261.62,65.42 v261.62,59.07
N$418  (via drill 0.6)
  Top 0.203: IC4.6 235.59,56.53 236.28,57.23 242.89,57.23 243.84,58.18 243.84,60.66 244.47,61.29 259.71,61.29 260.35,61.93 v260.35,65.42
  Top 0.229: v260.35,65.42 260.35,66.94 260.48,67.07 260.48,67.9 RN21.6
  Top 0.406: v260.35,59.07 IC1.3
  Bottom 0.406: v260.35,65.42 v260.35,59.07
N$419  (via drill 0.6)
  Top 0.203: IC4.5 234.31,56.53 235.52,57.73 242.25,57.73 243.21,58.69 243.21,61.29 243.84,61.93 258.44,61.93 259.08,62.56 v259.08,65.42
  Top 0.229: v259.08,65.42 259.08,66.56 259.59,67.07 259.59,67.85 RN21.5
  Top 0.406: v259.08,59.07 IC1.4
  Bottom 0.406: v259.08,59.07 v259.08,65.42
N$420  (via drill 0.6)
  Top 0.203: IC4.4 233.04,56.53 234.76,58.24 241.74,58.24 242.57,59.07 242.57,61.93 243.21,62.56 257.18,62.56 257.81,63.19 v257.81,65.42
  Top 0.229: v257.81,65.42 257.81,66.18 257.18,66.81 257.18,67.85 RN20.8
  Top 0.406: v257.81,59.07 IC1.5
  Bottom 0.406: v257.81,65.42 v257.81,59.07
N$421  (via drill 0.6)
  Top 0.203: IC4.3 231.78,56.53 234,58.75 241.24,58.75 241.94,59.45 241.94,62.56 242.57,63.19 255.91,63.19 256.54,63.83 v256.54,65.42
  Top 0.229: v256.54,65.42 256.54,66.56 256.29,66.81 256.29,67.9 RN20.7
  Top 0.406: v256.54,59.07 IC1.6
  Bottom 0.406: v256.54,65.42 v256.54,59.07
N$422  (via drill 0.6)
  Top 0.203: IC4.2 230.5,56.53 233.24,59.26 240.6,59.26 241.3,59.96 241.3,63.19 241.94,63.83 254.82,63.83 255.27,64.28 v255.27,65.42
  Top 0.229: IC1.7 255.27,57.16 | v255.27,65.42 255.27,66.43 255.52,66.69 255.52,67.9 RN20.6
  Top 0.406: 255.27,65.05 v255.27,65.42 | v255.27,59.07 IC1.7
  Bottom 0.406: v255.27,65.42 v255.27,59.07
N$423  (via drill 0.6)
  Top 0.203: IC4.1 229.24,56.53 232.6,59.89 240.09,59.89 240.66,60.46 240.66,63.76 241.38,64.47 253.55,64.47 254,64.91 v254,65.42
  Top 0.229: v254,65.42 254,66.43 254.63,67.07 254.63,67.85 RN20.5
  Top 0.406: v254,59.07 IC1.8
  Bottom 0.406: v254,59.07 v254,65.42
N$424  (via drill 0.5)
  Top 0.229: IC2.21 v133.35,49.35 133.35,47.26 132.96,46.88 120.02,46.88 119.38,47.51 IC5.1 | v148.59,43.83 150.26,43.83 RN22.5
  Bottom 0.229: v133.35,49.35 133.35,50.81 133.99,51.45 147.96,51.45 148.59,50.81 v148.59,43.83
N$425  (via drill 0.5)
  Top 0.229: IC5.2 118.11,47 118.75,46.37 134.62,46.37 v134.62,46.56 IC2.22 | RN22.6 147.4,42.96 v147.32,42.88
  Bottom 0.229: v147.32,42.88 147.32,50.18 146.69,50.81 135.25,50.81 134.62,50.18 v134.62,46.56
N$426  (via drill 0.5)
  Top 0.229: IC5.3 116.84,46.37 117.47,45.73 135.25,45.73 135.89,46.37 v135.89,46.56 IC2.23 | RN22.7 148.19,42.16 147.96,41.92 v146.05,41.92
  Bottom 0.229: v146.05,41.92 146.05,49.54 145.41,50.18 136.53,50.18 135.89,49.54 v135.89,46.56
N$427  (via drill 0.5)
  Top 0.229: IC5.4 115.57,45.73 116.2,45.1 136.53,45.1 137.16,45.73 v137.16,46.56 IC2.24 | RN22.8 148.34,41.36 147.96,40.97 145.1,40.97 v144.46,41.6
  Bottom 0.229: v144.46,41.6 144.46,48.83 143.75,49.54 137.79,49.54 137.16,48.91 v137.16,46.56
N$428  (via drill 0.5)
  Top 0.229: IC5.5 114.3,45.1 114.94,44.46 137.79,44.46 138.43,45.1 v138.43,46.56 IC2.25 | RN23.5 148.34,39.95 v148.27,40.02
  Bottom 0.229: v148.27,40.02 144.46,40.02 143.51,40.97 143.51,48.27 142.88,48.91 139.06,48.91 138.43,48.27 v138.43,46.56
N$429  (via drill 0.5)
  Top 0.229: IC5.6 113.03,44.46 113.67,43.83 139.06,43.83 139.7,44.46 v139.7,46.56 IC2.26 | RN23.6 147.4,39.15 v147.32,39.07
  Bottom 0.229: v147.32,39.07 144.15,39.07 142.56,40.65 142.56,47.56 141.85,48.27 140.03,48.27 IC2.26 v139.7,46.56
N$430  (via drill 0.5)
  Top 0.229: IC5.7 111.76,43.83 112.39,43.19 140.34,43.19 140.97,43.83 v140.97,46.56 IC2.27 | RN23.7 148.19,38.35 147.96,38.11 v146.05,38.11
  Bottom 0.229: v146.05,38.11 142.88,38.11 140.97,40.02 v140.97,46.56
N$431
  Top 0.229: IC2.28 142.24,43.19 | 142.24,43.19 141.6,42.56 111.12,42.56 110.49,43.19 IC5.8 | RN23.8 148.34,37.55 147.96,37.16 142.56,37.16 142.24,37.48 142.24,43.19
N$432  (via drill 0.6)
  Top 0.203: IC6.8 118.11,53 118.39,52.72 121.36,52.72 121.54,52.9 121.54,55.71 121.72,55.89 122.27,55.89 124.46,58.08 124.46,59.07 125.73,60.34 141.6,60.34 142.24,60.97 v142.24,65.42 | v142.24,59.07 IC2.1
  Top 0.229: v142.24,65.42 142.24,66.37 141.6,67 141.6,67.72 RN25.8
  Bottom 0.203: v142.24,65.42 v142.24,59.07
N$433  (via drill 0.6)
  Top 0.203: IC6.7 116.84,55.89 117.35,56.4 121.79,56.4 123.83,58.43 123.83,59.7 125.09,60.97 140.34,60.97 140.97,61.61 v140.97,65.42 | v140.97,59.07 IC2.2
  Top 0.229: v140.97,65.42 140.97,66.69 140.65,67 140.65,67.71 RN25.7
  Bottom 0.203: v140.97,65.42 v140.97,59.07
N$434  (via drill 0.6)
  Top 0.203: IC6.6 115.57,55.89 116.59,56.91 121.03,56.91 123.19,59.07 123.19,60.34 124.46,61.61 139.06,61.61 139.7,62.24 v139.7,65.42 | v139.7,59.07 IC2.3
  Top 0.229: v139.7,65.42 139.7,66.69 140.02,67 140.02,67.71 RN25.6
  Bottom 0.203: v139.7,65.42 v139.7,59.07
N$435  (via drill 0.6)
  Top 0.203: IC6.5 114.3,56.53 115.19,57.42 120.27,57.42 122.56,59.7 122.56,60.97 123.83,62.24 137.79,62.24 138.43,62.88 v138.43,65.42 | v138.43,59.07 IC2.4
  Top 0.229: v138.43,65.42 138.43,66.37 139.06,67 139.06,67.72 RN25.5
  Bottom 0.203: v138.43,65.42 v138.43,59.07
N$436  (via drill 0.6)
  Top 0.203: IC6.4 113.03,56.53 114.43,57.92 119.51,57.92 121.92,60.34 121.92,61.61 123.19,62.88 136.53,62.88 137.16,63.51 v137.16,65.42 | v137.16,59.07 IC2.5
  Top 0.229: v137.16,65.42 137.16,66.37 136.53,67 136.53,67.72 RN24.8
  Bottom 0.203: v137.16,65.42 v137.16,59.07
N$437  (via drill 0.6)
  Top 0.203: IC6.3 111.76,56.53 113.67,58.43 118.75,58.43 121.28,60.97 121.28,62.24 122.56,63.51 135.25,63.51 135.89,64.15 v135.89,65.42 | v135.89,59.07 IC2.6
  Top 0.229: v135.89,65.42 135.89,66.69 135.57,67 135.57,67.71 RN24.7
  Bottom 0.203: v135.89,65.42 v135.89,59.07
N$438  (via drill 0.6)
  Top 0.203: IC6.2 110.49,56.53 112.78,58.81 117.86,58.81 120.65,61.61 120.65,62.88 121.92,64.15 133.99,64.15 134.62,64.78 v134.62,65.42 | v134.62,59.07 IC2.7
  Top 0.229: v134.62,65.42 134.62,66.69 134.94,67 134.94,67.71 RN24.6
  Bottom 0.203: v134.62,65.42 v134.62,59.07
N$439  (via drill 0.6)
  Top 0.203: IC6.1 109.22,56.53 111.89,59.19 116.59,59.19 120.02,62.62 120.02,63.51 121.28,64.78 132.72,64.78 v133.35,65.42 | v133.35,59.07 IC2.8
  Top 0.229: v133.35,65.42 133.35,66.37 133.99,67 133.99,67.72 RN24.5
  Bottom 0.203: v133.35,65.42 v133.35,59.07
N$440
  Top 0.406: RN2.7 79.14,58.67 78.11,59.7 59.58,59.7 R30.C
N$441
  Top 0.406: RN5.1 209.62,60.27 208.91,60.97 182.76,60.97 R16.C
N$442
  Top 0.406: RN8.7 RN7.2
N$443
  Top 0.406: RN7.3 RN8.6
N$444
  Top 0.406: RN8.5 RN7.4
N$445
  Top 0.406: RN5.2 209.15,59.47 208.28,60.34 185.94,60.34 R15.C
N$446
  Top 0.406: RN4.3 77.87,54.86 75.56,57.16 72.28,57.16 R26.C
N$447
  Top 0.406: RN5.4 208.21,57.87 207.01,59.07 192.29,59.07 R13.C
N$448
  Top 0.406: RN5.5 RN6.4
N$449
  Top 0.406: RN7.1 RN8.8
N$450
  Top 0.406: RN8.1 208.35,56.46 206.38,58.43 195.47,58.43 R12.C
N$451
  Top 0.406: RN5.6 RN6.3
N$452
  Top 0.406: RN8.2 207.88,55.66 205.74,57.8 198.64,57.8 R11.C
N$453
  Top 0.406: RN6.2 RN5.7
N$454
  Top 0.406: RN5.8 RN6.1
N$455
  Top 0.406: RN3.4 RN4.5
N$456
  Top 0.406: RN2.5 80.08,60.27 79.38,60.97 53.23,60.97 R32.C
N$458
  Top 0.406: RN5.3 208.68,58.67 207.65,59.7 189.12,59.7 R14.C
N$459
  Top 0.406: RN8.3 207.41,54.86 205.1,57.16 201.81,57.16 R10.C
N$460
  Top 0.406: RN2.8 78.67,57.87 77.47,59.07 62.75,59.07 R29.C
N$461
  Top 0.406: RN4.1 78.81,56.46 76.83,58.43 65.92,58.43 R28.C
N$462
  Top 0.406: RN4.2 78.34,55.66 76.2,57.8 69.1,57.8 R27.C
N$463
  Top 0.406: RN12.4 RN11.5
N$464
  Top 0.305: R25.C 75.05,55.89
  Top 0.406: RN4.4 77.4,54.06 75.56,55.89 75.05,55.89
N$465
  Top 0.406: RN2.1 RN1.8
N$466
  Top 0.406: RN2.2 RN1.7
N$467
  Top 0.406: RN2.3 RN1.6
N$468
  Top 0.406: RN2.4 RN1.5
N$469
  Top 0.406: RN2.6 79.61,59.47 78.74,60.34 56.4,60.34 R31.C
N$470
  Top 0.406: RN8.4 206.94,54.06 205.1,55.89 204.59,55.89 R9.C
N$473
  Top 0.406: RN12.5 206.94,51.38 205.1,49.54 204.59,49.54 R1.C
N$474
  Top 0.406: RN11.6 RN12.3
N$475
  Top 0.406: RN12.6 207.41,50.58 205.1,48.27 201.81,48.27 R2.C
N$476
  Top 0.406: RN12.7 207.88,49.78 205.74,47.64 198.64,47.64 R3.C
N$477
  Top 0.406: RN9.4 RN10.5
N$478
  Top 0.406: RN10.6 RN9.3
N$479
  Top 0.406: RN9.2 RN10.7
N$480
  Top 0.406: RN10.8 RN9.1
N$481
  Top 0.406: RN12.2 RN11.7
N$482
  Top 0.406: RN10.1 208.21,47.57 207.01,46.37 192.29,46.37 R5.C
N$483
  Top 0.406: RN12.8 208.35,48.98 206.38,47 195.47,47 R4.C
N$484
  Top 0.406: RN10.3 209.15,45.97 208.28,45.1 185.94,45.1 R7.C
N$485
  Top 0.406: RN10.4 209.62,45.17 208.91,44.46 182.76,44.46 R8.C
N$486
  Top 0.406: RN10.2 208.68,46.77 207.65,45.73 189.12,45.73 R6.C
N$487
  Top 0.406: RN14.3 78.97,49.78 76.83,47.64 69.1,47.64 R19.C
N$488
  Top 0.406: RN14.2 78.5,50.58 76.2,48.27 72.28,48.27 R18.C
N$489
  Top 0.406: RN14.1 78.03,51.38 76.2,49.54 75.05,49.54 R17.C
N$490
  Top 0.406: RN16.4 80.72,45.17 80.01,44.46 53.23,44.46 R24.C
N$491
  Top 0.406: RN15.3 RN16.6
N$492
  Top 0.406: RN15.2 RN16.7
N$493
  Top 0.406: RN15.1 88.19,47.57 88.27,47.64 83.42,47.64 RN16.8
N$494
  Top 0.406: RN14.4 79.44,48.98 77.47,47 65.92,47 R20.C
N$495
  Top 0.406: RN16.3 80.25,45.97 79.38,45.1 56.4,45.1 R23.C
N$496
  Top 0.406: RN16.2 79.78,46.77 78.74,45.73 59.58,45.73 R22.C
N$497
  Top 0.406: RN16.1 79.31,47.57 78.11,46.37 62.75,46.37 R21.C
N$498  (via drill 0.6)
  Top 0.305: IC2.17 v128.27,50.18 | v244.47,50.18 244.47,51.45 245.11,52.08 v247.65,52.08 248.28,52.08 248.92,51.45 IC1.17 | U$13.B1 287.02,62.88 287.02,57.8 287.09,57.87 RN17.5 289.81,57.87 290.51,57.16 v290.51,52.08
  Bottom 0.305: v128.27,50.18 130.18,52.08 136.53,52.08 137.16,52.72 216.85,52.72 217.81,52.08 243.84,52.08 244.47,51.45 v244.47,50.18 | v247.65,52.08 v290.51,52.08
N$500
  Top 0.406: RN11.8 RN12.1
N$501
  Top 0.406: RN13.4 RN14.5
N$502
  Top 0.406: RN14.6 RN13.3
N$503
  Top 0.406: RN13.2 RN14.7
N$504
  Top 0.406: RN14.8 RN13.1
N$505
  Top 0.406: RN4.6 RN3.3
N$506
  Top 0.406: RN4.7 RN3.2
N$507
  Top 0.406: RN4.8 RN3.1
N$514
  Top 0.406: RN15.4 RN16.5
N$525  (via drill 0.5)
  Top 0.229: IC3.7 231.78,43.51 232.41,42.88 260.67,42.88 261.62,43.83 v261.62,46.62 IC1.27 | v266.7,40.97 270.43,40.97 RN18.7
  Bottom 0.229: v266.7,40.97 261.94,40.97 261.62,41.29 v261.62,46.62
N$526
  Top 0.229: IC1.28 262.89,42.88 | 262.89,42.88 262.25,42.24 231.14,42.24 230.5,42.88 IC3.8 | 262.89,42.88 262.89,40.65 263.52,40.02 270.91,40.02 RN18.8
OC_R1_A  (via drill 0.6)
  Top 0.406: IC3.18 v239.4,38.81 239.4,34.94 240.03,34.3 300.99,34.3 301.62,33.67 301.62,25.41 302.26,24.78 319.4,24.78 320.04,24.14 K1_B1.C1 | RN11.4 227.26,51.38 v227.46,51.19
  Bottom 0.406: v227.46,51.19 239.01,51.19 239.4,50.81 v239.4,38.81
OC_R1_B
  Top 0.203: RN7.5 226.13,54.06 232.73,60.66 237.17,60.66 238.12,61.61 IC4.11
  Top 0.406: IC4.11 238.12,69.23 238.76,69.86 249.56,69.86 250.19,70.5 297.81,70.5 299.08,71.77 322.58,71.77 323.21,72.4 323.21,81.93 323.85,82.56 K1_B2.C1
OC_R1_C  (via drill 0.6)
  Top 0.406: RN13.8 106.61,51.38 v106.68,51.45 | IC5.18 v119.38,38.75 119.38,36.21 120.65,34.94 148.59,34.94 149.22,34.3 149.22,23.51 149.86,22.87 K1_B3.C1
  Bottom 0.406: v106.68,51.45 118.11,51.45 119.38,50.18 v119.38,38.75
OC_R1_D
  Top 0.203: RN3.5 105.48,54.06 111.12,59.7 115.57,59.7 118.11,62.24 IC6.11
  Top 0.406: IC6.11 118.11,69.86 118.75,70.5 153.67,70.5 154.31,71.13 154.31,81.93 154.94,82.56 K1_B4.C1
OC_R2_A  (via drill 0.6)
  Top 0.406: RN11.3 225.66,50.58 v226.06,50.18 | IC3.17 v238.12,38.81 238.17,38.77 238.17,34.33 238.85,33.67 300.36,33.67 300.99,33.03 300.99,23.51 301.62,22.87 K2_B1.C1
  Bottom 0.406: v226.06,50.18 236.85,50.18 238.12,48.91 v238.12,38.81
OC_R2_B
  Top 0.203: IC4.12 236.85,62.24 235.9,61.29 232.73,61.29 226.29,54.86 RN7.6
  Top 0.406: IC4.12 236.85,69.86 237.49,70.5 248.92,70.5 249.56,71.13 297.18,71.13 298.45,72.4 307.34,72.4 307.98,73.04 307.98,81.93 308.61,82.56 K2_B2.C1
OC_R2_C  (via drill 0.6)
  Top 0.406: RN13.7 105.01,50.58 v105.41,50.18 | IC5.17 v118.11,38.75 118.11,34.94 119.38,33.67 133.35,33.67 133.99,33.03 133.99,23.51 134.62,22.87 K2_B3.C1
  Bottom 0.406: v105.41,50.18 115.57,50.18 118.11,47.64 v118.11,38.75
OC_R2_D
  Top 0.203: RN3.6 105.01,54.86 110.49,60.34 114.3,60.34 116.84,62.88 IC6.12
  Top 0.406: IC6.12 116.84,70.82 117.47,71.45 138.75,71.45 139.06,71.77 139.06,81.93 139.7,82.56 K2_B4.C1
OC_R3_A  (via drill 0.6)
  Top 0.406: RN11.2 223.92,49.78 v224.79,48.91 | IC3.16 v236.85,38.81 236.85,33.67 237.49,33.03 287.02,33.03 287.65,32.4 287.65,23.51 288.29,22.87 K3_B1.C1
  Bottom 0.406: v224.79,48.91 235.59,48.91 236.85,47.64 v236.85,38.81
OC_R3_B
  Top 0.203: RN7.7 226.46,55.66 232.73,61.93 235.27,61.93 235.59,62.24 IC4.13
  Top 0.406: IC4.13 235.59,70.5 236.22,71.13 248.28,71.13 248.92,71.77 292.1,71.77 292.74,72.4 292.74,81.93 293.37,82.56 K3_B2.C1
OC_R3_C  (via drill 0.6)
  Top 0.406: RN13.6 103.27,49.78 v104.14,48.91 | IC5.16 v116.84,38.75 116.84,34.3 118.75,32.4 118.75,23.51 119.38,22.87 K3_B3.C1
  Bottom 0.406: v104.14,48.91 114.3,48.91 116.84,46.37 v116.84,38.75
OC_R3_D
  Top 0.203: RN3.7 104.54,55.66 109.73,60.85 112.9,60.85 115.57,63.51 IC6.13
  Top 0.406: IC6.13 115.57,71.13 116.84,72.4 123.19,72.4 123.83,73.04 123.83,81.93 124.46,82.56 K3_B4.C1
OC_R4_A  (via drill 0.6)
  Top 0.406: RN11.1 222.18,48.98 v223.52,47.64 | IC3.15 v235.59,38.81 235.59,33.67 236.85,32.4 271.78,32.4 272.42,31.76 272.42,23.51 273.05,22.87 K4_B1.C1
  Bottom 0.406: v223.52,47.64 234.31,47.64 235.59,46.37 v235.59,38.81
OC_R4_B
  Top 0.203: RN7.8 226.62,56.46 232.73,62.56 234,62.56 234.31,62.88 IC4.14
  Top 0.406: IC4.14 234.31,71.13 234.95,71.77 247.65,71.77 248.6,72.72 277.18,72.72 277.5,73.04 277.5,81.93 278.13,82.56 K4_B2.C1
OC_R4_C  (via drill 0.6)
  Top 0.406: RN13.5 101.53,48.98 v102.87,47.64 | IC5.15 v115.57,38.75 115.57,33.67 114.94,33.03 109.86,33.03 109.22,33.03 108.58,33.03 107.95,32.4 107.95,23.51 107.31,22.87 K4_B3.C1
  Bottom 0.406: v102.87,47.64 113.03,47.64 115.57,45.1 v115.57,38.75
OC_R4_D
  Top 0.203: IC6.14 114.3,63.13 112.52,61.35 109.47,61.35 104.65,56.53 89.77,56.53 RN3.8
  Top 0.406: IC6.14 114.3,70.5 113.03,71.77 113.03,81.93 112.39,82.56 K4_B4.C1
OC_R5_A  (via drill 0.6)
  Top 0.406: RN9.8 221.05,47.57 222.25,46.37 v227.33,46.37 | IC3.14 v234.31,38.81 234.31,33.67 233.68,33.03 233.68,23.51 234.31,22.87 K5_B1.C1
  Bottom 0.406: v227.33,46.37 233.04,46.37 234.31,45.1 v234.31,38.81
OC_R5_B
  Top 0.203: IC4.15 233.04,63.51 232.73,63.19 232.41,63.19 227.08,57.87 RN6.5
  Top 0.406: IC4.15 233.04,71.77 233.68,72.4 242.57,72.4 243.21,73.04 243.21,81.93 242.57,82.56 K5_B2.C1
OC_R5_C  (via drill 0.6)
  Top 0.406: IC5.14 v114.3,38.75 114.3,34.94 113.67,34.3 69.85,34.3 69.22,33.67 69.22,23.51 68.58,22.87 K5_B3.C1 | RN15.8 101.03,47.57 102.23,46.37 v106.68,46.37
  Bottom 0.406: v106.68,46.37 112.39,46.37 114.3,44.46 v114.3,38.75
OC_R5_D
  Top 0.203: IC6.15 113.03,63 112.01,61.99 109.09,61.99 105.03,57.92 89.76,57.92 RN1.1
  Top 0.406: IC6.15 113.03,69.23 110.49,71.77 74.93,71.77 74.3,72.4 74.3,81.93 73.66,82.56 K5_B4.C1
OC_R6_A  (via drill 0.6)
  Top 0.406: RN9.7 220.58,46.77 222.25,45.1 v226.06,45.1 | IC3.13 v233.04,38.81 233.04,34.94 232.41,34.3 223.52,34.3 222.88,33.67 222.88,23.51 222.25,22.87 K6_B1.C1
  Bottom 0.406: v226.06,45.1 231.78,45.1 233.04,43.83 v233.04,38.81
OC_R6_B
  Top 0.203: RN6.6 226.93,58.67 231.78,63.51 IC4.16
  Top 0.406: IC4.16 231.78,71.13 230.5,72.4 228.6,72.4 227.97,73.04 227.97,81.93 227.33,82.56 K6_B2.C1
OC_R6_C  (via drill 0.6)
  Top 0.406: IC5.13 v113.03,38.75 113.03,36.21 112.39,35.57 55.24,35.57 53.98,34.3 53.98,23.51 53.34,22.87 K6_B3.C1 | RN15.7 100.56,46.77 102.23,45.1 v105.41,45.1
  Bottom 0.406: v105.41,45.1 111.76,45.1 113.03,43.83 v113.03,38.75
OC_R6_D
  Top 0.203: IC6.16 111.76,63 111.25,62.5 108.71,62.5 105.03,58.81 89.85,58.81 RN1.2
  Top 0.406: IC6.16 111.76,68.59 109.86,70.5 59.69,70.5 59.05,71.13 59.05,81.93 58.42,82.56 K6_B4.C1
OC_R7_A  (via drill 0.6)
  Top 0.406: RN9.6 220.11,45.97 222.25,43.83 v224.79,43.83 | IC3.12 v231.78,38.81 231.78,36.21 231.14,35.57 208.28,35.57 207.65,34.94 207.65,23.51 207.01,22.87 K7_B1.C1
  Bottom 0.406: v224.79,43.83 230.5,43.83 231.78,42.56 v231.78,38.81
OC_R7_B
  Top 0.203: RN6.7 226.78,59.47 230.5,63.19 IC4.17
  Top 0.406: IC4.17 230.5,70.5 229.87,71.13 213.36,71.13 212.72,71.77 212.72,81.93 212.09,82.56 K7_B2.C1
OC_R7_C  (via drill 0.6)
  Top 0.406: v111.76,38.75 IC5.12 111.76,37.61 110.87,36.72 40.39,36.72 39.24,36.72 38.73,36.21 38.73,23.51 38.1,22.87 K7_B3.C1 | RN15.6 100.09,45.97 102.23,43.83 v104.14,43.83
  Bottom 0.406: v104.14,43.83 110.49,43.83 111.76,42.56 v111.76,38.75
OC_R7_D
  Top 0.203: IC6.17 110.49,63.39 110.11,63 108.58,63 105.03,59.45 89.72,59.45 RN1.3
  Top 0.406: IC6.17 110.49,67.96 109.22,69.23 44.45,69.23 43.81,69.86 43.81,81.93 43.18,82.56 K7_B4.C1
OC_R8_A  (via drill 0.6)
  Top 0.406: RN9.5 219.64,45.17 222.25,42.56 v223.52,42.56 | IC3.11 v230.5,38.81 230.5,37.48 229.87,36.84 193.04,36.84 192.41,36.21 192.41,23.51 191.77,22.87 K8_B1.C1
  Bottom 0.406: v223.52,42.56 229.24,42.56 230.5,41.29 v230.5,38.81
OC_R8_B
  Top 0.203: RN6.8 226.62,60.27 229.24,62.88 IC4.18
  Top 0.406: IC4.18 229.24,69.86 228.6,70.5 198.12,70.5 197.49,71.13 197.49,81.93 196.85,82.56 K8_B2.C1
OC_R8_C  (via drill 0.6)
  Top 0.406: v110.49,38.75 IC5.11 110.49,41.92 109.86,42.56 107.95,42.56 107.31,41.92 107.31,38.75 106.68,38.11 24.13,38.11 23.5,37.48 23.5,23.51 22.86,22.87 K8_B3.C1 | RN15.5 99.62,45.17 102.23,42.56 v102.87,42.56
  Bottom 0.406: v102.87,42.56 109.22,42.56 110.49,41.29 v110.49,38.75
OC_R8_D
  Top 0.203: RN1.4 104.96,60.27 107.57,62.88 107.57,63.21 108.97,64.6 IC6.18
  Top 0.406: IC6.18 109.22,66.69 107.95,67.96 29.84,67.96 28.57,69.23 28.57,81.93 27.94,82.56 K8_B4.C1
REG_5V  (via drill 0.5, 0.6, 0.9)
  Top 0.254: 286.38,67.96 285.75,67.32 285.75,67 U$13.A2 | RNE1.6 RNE1.5 | RNB1.6 296.72,68.42 v296.55,68.59
  Top 0.305: IC2.15 v125.73,53.99 126.36,53.99 129.54,50.81 129.54,47.64 | 250.19,53.99 251.46,55.26 252.09,55.26 252.73,55.89 | IC2.9 132.08,56.53 v130.81,55.26 | IC1.18 v250.19,53.35 | IC1.9 252.73,55.89 | 252.73,55.89 253.37,55.26 263.84,55.26 264.16,55.26 265.43,56.53 270.51,56.53 | 270.51,56.53 281.31,56.53 284.48,59.7 285.75,59.7 285.99,59.47 | 286.22,63.68 U$13.B2 U$13.A2 | C1.1 270.6,56.44 270.51,56.53
  Top 0.406: C2.1 C3.1 | C4.1 C1.1 | IC2.18 129.54,50.81 130.18,51.45 144.55,51.45 | C8.1 144.55,51.45 | 144.55,51.45 C5.1 144.55,45.96 144.78,45.73 149.54,45.73 149.86,46.05 149.86,46.37 | C6.1 C7.1 265.2,54.22 264.16,55.26 | 149.86,47.64 149.86,47.72 | 149.86,47.72 C3.1 | C3.1 149.86,47.96 149.86,47.72 | RNE1.5 317.97,58.9 318.77,59.7 X26.2
  Top 0.813: H1.1 311.63,36.69 v311.15,36.21 | IC7.4 302.39,38.87 | 302.39,38.87 v302.26,38.75 | 302.39,38.87 299.32,38.87 C10.1
  Top 1.016: 154.94,45.73 150.18,45.73 149.86,46.05 | 149.86,46.37 149.86,47.64 | C24.+ 156.21,47 154.94,45.73 | C28.+ 156.21,44.46 154.94,45.73 | C1.1 270.6,48.18 271.4,47.38 275.46,47.38 276.23,46.62 276.23,46.37 | 276.23,46.37 C25.+ | 344.55,59.7 345.19,59.7 345.19,66.43 344.3,67.32 S1.1 | C27.+ 284.48,45.1 283.21,46.37 276.23,46.37 | C26.+ 269.24,56.85
  Top 1.27: v296.55,68.59 287.34,68.59 285.75,67 U$13.B2 285.75,60.02 284.16,60.02 280.99,56.85 269.24,56.85 265.43,56.85 263.84,55.26 253.05,55.26 252.73,55.58 251.78,55.58 250.19,53.99 v250.19,53.35 | H1.1 320.52,36.69 v320.68,36.84
  Top 1.778: X26.2 v337.19,59.7 344.55,59.7
  Bottom 0.305: v250.19,53.35 219.07,53.35 218.44,53.99 135.89,53.99 135.25,53.35 133.99,53.35 133.35,53.99 v125.73,53.99 125.73,54.62 126.36,55.26 v130.81,55.26
  Bottom 0.813: v311.15,36.21 302.26,36.21 v302.26,38.75 | 312.42,55.89 312.42,60.97 311.15,62.24 v307.98,62.24
  Bottom 1.016: v307.98,62.24 298.45,62.24 296.55,64.15 v296.55,68.59
  Bottom 1.27: v320.68,36.84 312.42,45.1 312.42,55.89 316.23,59.7 v337.19,59.7
REG_12V  (via drill 0.5)
  Top 0.813: BRA2.+ 327.02,40.02 325.75,38.75 316.23,38.75 313.69,41.29 311.4,41.29 v311.28,41.41 IC7.7 | C9.1 308.61,49.54 v310.51,47.64
  Bottom 0.813: v310.51,47.64 310.51,42.05 311.15,41.41 v311.28,41.41
UNREG_12V  (via drill 0.6)
  Top 0.254: 336.55,29.22 337.19,28.59
  Top 0.305: 204.47,52.72 R1.A
  Top 0.406: IC5.10 v109.22,38.75 | IC6.10 119.38,66.05 v120.02,66.69 | IC4.10 v239.4,62.56 | R8.A 177.8,52.72 | R15.A 181.61,52.72 | R6.A 185.42,52.72 | 189.23,52.72 R13.A | R4.A 193.04,52.72 | R3.A 196.85,52.72 | R2.A 200.66,52.72 | R16.A 177.8,52.72 | 177.8,52.72 181.61,52.72 | R7.A 181.61,52.72 | 181.61,52.72 185.42,52.72 | R14.A 185.42,52.72 | 185.42,52.72 189.23,52.72 | R5.A 189.23,52.72 | 189.23,52.72 193.04,52.72 | R12.A 193.04,52.72 | 193.04,52.72 196.85,52.72 | R11.A 196.85,52.72 | 196.85,52.72 200.66,52.72 | R10.A 200.66,52.72 | R24.A 48.26,52.72 | R31.A 52.07,52.72 | R30.A 55.88,52.72 | R29.A 59.69,52.72 | R28.A 63.5,52.72 | v67.31,52.72 R19.A | 71.12,52.72 R18.A | R25.A 74.93,52.72 | 74.93,52.72 R17.A | R32.A 48.26,52.72 | 48.26,52.72 52.07,52.72 | R23.A 52.07,52.72 | 52.07,52.72 55.88,52.72 | R22.A 55.88,52.72 | 55.88,52.72 59.69,52.72 | R21.A 59.69,52.72 | 59.69,52.72 63.5,52.72 | R20.A 63.5,52.72 | 63.5,52.72 v67.31,52.72 | v67.31,52.72 71.12,52.72 | R26.A 71.12,52.72 | 71.12,52.72 74.93,52.72 | R9.A 204.47,52.72 | 204.47,50.81 204.47,52.72 | 204.47,52.72 202.25,52.72 | 200.66,52.72 202.25,52.72 | 202.25,52.72 v202.25,49.54 | IC3.10 229.24,39.38 v229.2,38.81 | R27.A v67.31,52.72
  Top 2.54: BRA2.~@2 BRA2.~@1 331.42,36.21 U$14.TIP | X25.2 341.94,29.22 336.55,29.22 333.38,32.4 333.38,36.84 332.74,37.48
  Bottom 0.254: 332.74,38.73 332.74,37.99 U$14.TIP
  Bottom 0.406: v239.4,62.56 239.4,71.13 238.76,71.77 | v202.25,49.54 202.25,33.67 | 229.3,33.99 229.62,33.67 | v67.31,52.72 67.31,33.67
  Bottom 0.813: v109.22,38.75 109.22,33.67
  Bottom 1.016: 229.3,33.99 229.2,33.99 v229.2,38.81 | 220.34,71.13 219.71,71.77 | 31.11,71.13 31.75,71.77 | C22.+ 171.45,34.3 170.81,33.67 | C23.+ 219.07,71.77 | C21.+ 147.96,71.77 | C20.+ 12.7,43.19 | C19.+ 12.7,66.69 | K8_B4.C2 19.68,82.56 19.05,81.93 19.05,71.77 | K7_B4.C2 34.92,82.56 34.29,81.93 34.29,72.4 33.66,71.77 | K6_B4.C2 50.16,82.56 49.53,81.93 49.53,71.77 | K5_B4.C2 65.41,82.56 64.77,81.93 64.77,72.4 64.14,71.77 | K4_B4.C2 104.14,82.56 103.5,81.93 103.5,71.77 | K3_B4.C2 119.38,82.56 118.75,81.93 118.75,71.77 | K2_B4.C2 134.62,82.56 133.99,81.93 133.99,72.4 134.62,71.77 | K1_B4.C2 149.86,82.56 149.22,81.93 149.22,72.4 149.86,71.77 | K8_B2.C2 188.59,82.56 187.96,81.93 187.96,71.77 | K7_B2.C2 203.84,82.56 203.2,81.93 203.2,72.4 203.84,72.4 204.47,71.77 | K6_B2.C2 219.07,82.56 218.44,81.93 218.44,71.77 | K5_B2.C2 234.31,82.56 233.68,81.93 233.68,72.4 233.04,71.77 | K4_B2.C2 273.05,82.56 272.42,81.93 272.42,71.77 | K3_B2.C2 288.29,82.56 287.65,81.93 287.65,71.77 288.29,71.77 289.56,73.04 302.89,73.04 | K2_B2.C2 303.53,82.56 302.89,81.93 302.89,73.04 | K1_B1.C2 327.02,22.87 327.66,23.51 327.66,33.67 | K2_B1.C2 311.79,22.87 312.42,23.51 312.42,33.03 313.06,33.67 | K3_B1.C2 296.55,22.87 297.18,23.51 297.18,33.03 297.81,33.67 | K4_B1.C2 281.31,22.87 281.94,23.51 281.94,33.03 282.57,33.67 | K5_B1.C2 242.57,22.87 243.21,23.51 243.21,33.67 | K6_B1.C2 227.33,22.87 227.97,23.51 227.97,33.67 | K7_B1.C2 212.09,22.87 212.72,23.51 212.72,33.67 | K8_B1.C2 196.85,22.87 197.49,23.51 197.49,33.03 196.85,33.67 | K1_B3.C2 158.75,22.87 159.38,23.51 159.38,33.67 | K2_B3.C2 142.88,22.87 143.51,23.51 143.51,33.67
  Bottom 1.016: K3_B3.C2 127.64,22.87 128.27,23.51 128.27,33.03 128.91,33.67 | K4_B3.C2 112.39,22.87 113.03,23.51 113.03,33.67 | K5_B3.C2 73.66,22.87 74.3,23.51 74.3,33.03 74.93,33.67 | K6_B3.C2 58.42,22.87 59.05,23.51 59.05,33.67 | K7_B3.C2 43.18,22.87 43.81,23.51 43.81,33.67 | K8_B3.C2 27.94,22.87 28.57,23.51 28.57,33.67 | K1_B2.C2 318.77,82.56 318.13,81.93 318.13,74.31 316.87,73.04 302.89,73.04
  Bottom 1.27: v120.02,66.69 120.02,71.77
  Bottom 2.54: 332.74,33.67 332.36,33.29 336.13,29.52 X25.2 | 332.74,33.67 327.66,33.67 313.06,33.67 297.81,33.67 282.57,33.67 243.21,33.67 229.62,33.67 227.97,33.67 212.72,33.67 202.25,33.67 196.85,33.67 170.81,33.67 159.38,33.67 143.51,33.67 128.91,33.67 113.03,33.67 109.22,33.67 74.93,33.67 67.31,33.67 59.05,33.67 43.81,33.67 28.57,33.67 12.7,33.67 12.7,43.19 12.7,66.69 12.7,71.77 19.05,71.77 31.75,71.77 33.66,71.77 49.53,71.77 64.14,71.77 103.5,71.77 118.75,71.77 120.02,71.77 134.62,71.77 147.96,71.77 149.86,71.77 187.96,71.77 204.47,71.77 218.44,71.77 219.07,71.77 219.71,71.77 233.04,71.77 238.76,71.77 272.42,71.77 287.65,71.77 | 332.13,33.33 332.74,33.67 | 332.74,33.67 332.74,38.73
